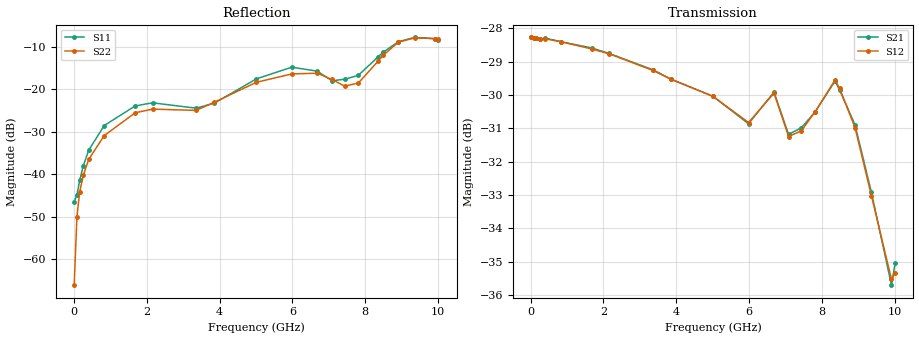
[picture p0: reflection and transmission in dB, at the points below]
! Device ID: PE43705
! Serial: 1
! Insertion: A
! Impedance: 50 ohm
! Temp: 25C
! VDD: 3.400V
! Attenuation Step: 27.25dB
#  Hz  S  RI  R  50
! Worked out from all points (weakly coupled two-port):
!   401 points, 10 MHz to 10.01 GHz, reference 50 ohm
!   highest |S21| = -28.26 dB at 10 MHz (marker M1); lowest = -35.7 dB at 9.91 GHz (marker M2)
!   lowest |S11| = -46.5 dB at 10 MHz (marker M3), VSWR 1.01, Z = 49.5 + j0.0498 ohm
!   |S11| at or under -10 dB: start of sweep to 8.671 GHz
!   |S22| runs from -66.2 to -7.8 dB; largest |S21 - S12| = 0.00066
!   S11 on the Smith chart (normalised r, x): 10 MHz: 0.99, +0.00; 7.435 GHz: 0.82, +0.16; 8.485 GHz: 0.84, +0.49; 9.36 GHz: 0.55, +0.49; 10.01 GHz: 0.49, +0.27
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1e7  -0.00472 0.000502  0.0386 -0.000105  0.0386 -9.98e-05  -0.000211 0.000443
8.5e7  -0.00442 0.00355  0.0385 -0.000875  0.0385 -0.000846  0.000349 0.00314
1.6e8  -0.0048 0.00692  0.0385 -0.00161  0.0385 -0.00159  0.0001 0.00614
2.6e8  -0.00595 0.0111  0.0383 -0.0026  0.0383 -0.00256  -0.000985 0.0097
4.1e8  -0.00897 0.017  0.0383 -0.00384  0.0382 -0.00403  -0.00366 0.0145
8.35e8  -0.0259 0.0271  0.0372 -0.00788  0.0372 -0.00786  -0.0184 0.0218
1.685e9  -0.0613 0.0176  0.0341 -0.0149  0.034 -0.0148  -0.0516 0.0119
2.16e9  -0.0693 0.00429  0.0316 -0.0183  0.0316 -0.0182  -0.0585 0.000882
3.36e9  -0.0598 0.00496  0.024 -0.0248  0.024 -0.0247  -0.0563 0.00508
3.86e9  -0.063 0.0278  0.0206 -0.0263  0.0207 -0.0262  -0.0677 0.0202
5.01e9  -0.0993 0.0885  0.0144 -0.028  0.0144 -0.028  -0.1054 0.0599
5.985e9  -0.1506 0.1033  0.00832 -0.0274  0.00843 -0.0275  -0.1319 0.076
6.685e9  -0.1415 0.0828  0.00597 -0.0314  0.00585 -0.0313  -0.1381 0.0708
7.085e9  -0.1082 0.0652  0.000383 -0.0276  0.000258 -0.0274  -0.108 0.0739
7.435e9  -0.0893 0.0969  0.00152 -0.0282  0.00174 -0.0279  -0.0732 0.0811
7.81e9  -0.0422 0.1401  0.00109 -0.0298  0.00122 -0.0298  -0.0462 0.1094
8.36e9  -0.00876 0.2434  -0.00719 -0.0324  -0.00733 -0.0325  -0.0333 0.2144
8.485e9  -0.0148 0.273  -0.00969 -0.0307  -0.00933 -0.031  -0.0409 0.2477
8.91e9  -0.071 0.358  -0.0141 -0.0248  -0.0139 -0.0246  -0.1031 0.346
9.36e9  -0.1708 0.3734  -0.0131 -0.0184  -0.0128 -0.0183  -0.1963 0.3539
9.91e9  -0.2892 0.2706  -0.00439 -0.0158  -0.00455 -0.0161  -0.3284 0.2246
1.001e10  -0.3018 0.2367  -0.00317 -0.0174  -0.00332 -0.0168  -0.345 0.1854
